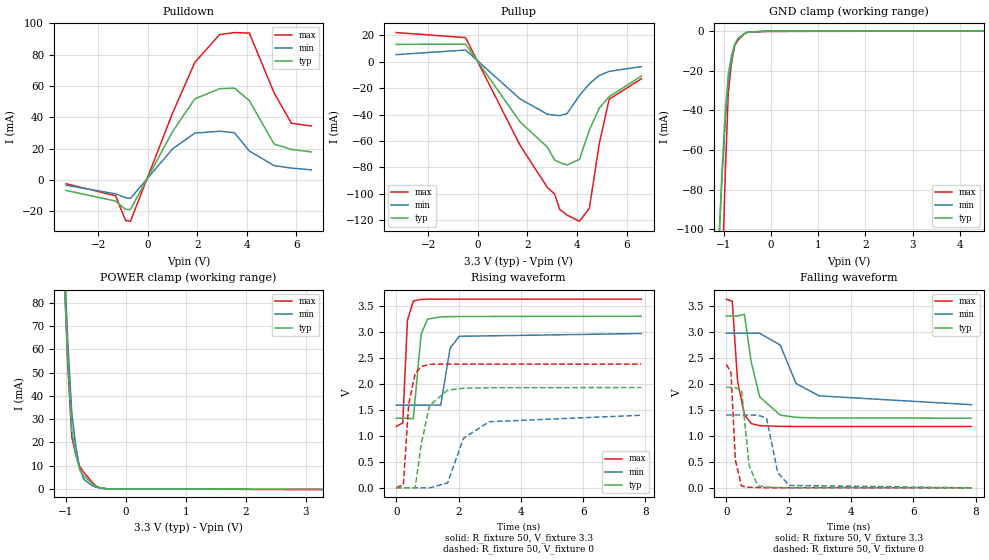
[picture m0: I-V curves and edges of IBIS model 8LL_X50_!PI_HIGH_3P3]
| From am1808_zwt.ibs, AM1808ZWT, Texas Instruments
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|   Model Cell 8LL_X50_!PI_HIGH_3P3
|BC1833DV40CTPBFZ_!PI_HIGH_3P3
[Model]   8LL_X50_!PI_HIGH_3P3
Model_type   I/O
Polarity   Non-Inverting
Enable   Active-Low
Vinl =  0.8V
Vinh =  2V
Cref =  15pF
Rref =  100.00M
Vref =  0V
Vmeas =  1.65
C_comp   1.943144p   1.721292p   2.064363p
[Model Spec]
Vinl   0.8V   0.8V   0.8V
Vinh   2V   2V   2V
[Temperature Range]   25   125   -40
[Voltage Range]   3.3   2.97   3.63
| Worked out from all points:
|   slope of the pulldown table from 0 to 0.495 V, typ, clamps not added: 31.5 ohm
|   slope of the pullup table from 0 to 0.495 V, typ, clamps not added: 35.2 ohm
|   GND clamp passes 1 mA (typ) near -0.52 V on its own axis
|   POWER clamp passes 1 mA (typ) near -0.48 V on its own axis
|   rising waveform, R_fixture 50, V_fixture 3.3: 20-80 % time 145ps typ, 208ps min, 98.5ps max; typ from 1.34 V to 3.3 V
|   rising waveform, R_fixture 50, V_fixture 0: 20-80 % time 316ps typ, 691ps min, 182ps max; typ from 0.003 V to 1.93 V
|   falling waveform, R_fixture 50, V_fixture 3.3: 20-80 % time 387ps typ, 781ps min, 207ps max; typ from 3.3 V to 1.34 V
|   falling waveform, R_fixture 50, V_fixture 0: 20-80 % time 167ps typ, 250ps min, 117ps max; typ from 1.93 V to 0.003 V
[POWER_clamp]
|   voltage   I(typ)   I(min)   I(max)
-3.3V     2.432A     2.868A     2.62A
-1.033V   95.08mA    103.2mA    96.86mA
-966.7mV  54.92mA    63.38mA    53.03mA
-900mV    25.2mA     32.75mA    22.33mA
-833.3mV  14.74mA    18.43mA    14.71mA
-766.7mV  8.2mA      8.88mA     9.666mA
-700mV    5.589mA    4.11mA     7.198mA
-566.7mV  2.493mA    1.586mA    3.095mA
-500mV    1.194mA    763.3uA    1.351mA
-433.3mV  536.4uA    365.2uA    570.9uA
-300mV    29.89uA    27.56uA    34.63uA
3.3V      -177.5uA   -143.2uA   -277.3uA
[Pulldown]
|   voltage   I(typ)   I(min)   I(max)
-3.3V     -6.708mA   -3.419mA   -2.439mA
-1.3V     -13.52mA   -8.874mA   -10.14mA
-900mV    -18.83mA   -11.38mA   -25.87mA
-700mV    -18.88mA   -11.81mA   -26.45mA
1V        30.91mA    19.84mA    42.7mA
1.9V      51.83mA    29.94mA    75.14mA
2.9V      58.3mA     31.12mA    92.92mA
3.5V      58.67mA    30.17mA    94.2mA
4.1V      50.73mA    18.46mA    93.88mA
5.1V      22.94mA    9.149mA    55.64mA
5.8V      19.5mA     7.56mA     36.23mA
6.6V      17.91mA    6.449mA    34.47mA
[Pullup]
|   voltage   I(typ)   I(min)   I(max)
-3.3V     13.07mA    5.31mA     22.02mA
-500mV    13.27mA    8.819mA    18.19mA
1.7V      -45.56mA   -28.16mA   -63.21mA
2.8V      -64.62mA   -39.71mA   -95.04mA
3.1V      -74.46mA   -40.51mA   -100.2mA
3.3V      -76.24mA   -40.86mA   -111.7mA
3.6V      -78.17mA   -39.29mA   -116.1mA
4.1V      -73.95mA   -25.59mA   -120.8mA
4.5V      -51.77mA   -16.71mA   -110.9mA
4.9V      -35.15mA   -10.47mA   -62.03mA
5.3V      -26.46mA   -7.311mA   -28.43mA
6.6V      -10.91mA   -3.736mA   -12.96mA
[GND_clamp]
|   voltage   I(typ)   I(min)   I(max)
-3.3V     -2.048A    -1.805A    -3.667A
-1.1V     -108.7mA   -106.5mA   -191.5mA
-1.033V   -71.21mA   -74.08mA   -127.8mA
-966.7mV  -42.29mA   -46.88mA   -74.43mA
-900mV    -21.88mA   -24.94mA   -31.36mA
-833.3mV  -12.75mA   -14.54mA   -16.38mA
-766.7mV  -6.878mA   -7.55mA    -7.563mA
-700mV    -4.259mA   -3.967mA   -4.917mA
-566.7mV  -1.601mA   -1.572mA   -1.659mA
-500mV    -700.3uA   -785.3uA   -703.8uA
-33.33mV  0A         0A         -307.8uA
6.6V      0A         0A         0A
[Ramp]
| variable   typ   min   max
dV/dt_f   1.211508/0.3850807n  0.8580562/0.7859809n   1.483343/0.2064522n
dV/dt_r   1.164498/0.3153508n  0.8460027/0.6937386n   1.433511/0.1813636n
R_load = 50
[Rising Waveform]
R_fixture = 50
V_fixture = 3.3
V_fixture_min = 2.97
V_fixture_max = 3.63
|   time   V(typ)   V(min)   V(max)
0s        1.34V      1.592V     1.181V
210ps     1.34V      1.592V     1.251V
360ps     1.34V      1.592V     3.221V
550ps     1.332V     1.592V     3.595V
800ps     2.956V     1.592V     3.625V
1.01ns    3.247V     1.592V     3.628V
1.43ns    3.289V     1.595V     3.629V
1.73ns    3.294V     2.685V     3.63V
2.02ns    3.296V     2.915V     3.63V
7.87ns    3.3V       2.969V     3.63V
[Rising Waveform]
R_fixture = 50
V_fixture = 0
V_fixture_min = 0
V_fixture_max = 0
|   time   V(typ)   V(min)   V(max)
0s        3.384mV    2.145mV    4.749mV
230ps     3.385mV    2.145mV    66.55mV
400ps     2.943mV    2.144mV    1.608V
610ps     4.219mV    2.145mV    2.201V
800ps     831.6mV    2.145mV    2.334V
1.07ns    1.585V     2.116mV    2.377V
1.65ns    1.88V      96.58mV    2.381V
2.16ns    1.916V     956mV      2.381V
2.98ns    1.928V     1.273V     2.381V
7.87ns    1.931V     1.398V     2.381V
[Falling Waveform]
R_fixture = 50
V_fixture = 3.3
V_fixture_min = 2.97
V_fixture_max = 3.63
|   time   V(typ)   V(min)   V(max)
0s        3.3V       2.97V      3.623V
190ps     3.298V     2.97V      3.582V
360ps     3.301V     2.97V      2.056V
580ps     3.331V     2.97V      1.407V
800ps     2.413V     2.968V     1.236V
1.07ns    1.748V     2.968V     1.196V
1.73ns    1.399V     2.743V     1.182V
2.24ns    1.355V     2.004V     1.181V
2.98ns    1.343V     1.768V     1.181V
7.87ns    1.34V      1.598V     1.181V
[Falling Waveform]
R_fixture = 50
V_fixture = 0
V_fixture_min = 0
V_fixture_max = 0
|   time   V(typ)   V(min)   V(max)
0s        1.931V     1.401V     2.373V
150ps     1.928V     1.401V     2.21V
290ps     1.926V     1.401V     534.1mV
490ps     1.873V     1.401V     37.21mV
730ps     437.6mV    1.399V     13.76mV
1.01ns    42.91mV    1.398V     7.517mV
1.29ns    17.59mV    1.341V     5.782mV
1.65ns    9.714mV    295mV      5.118mV
2.02ns    6.553mV    49.31mV    4.901mV
7.87ns    3.392mV    3.112mV    4.75mV
